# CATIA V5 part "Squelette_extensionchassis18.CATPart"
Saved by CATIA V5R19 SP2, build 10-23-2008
Part number: Squelette_extensionchassis18
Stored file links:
  G:\Documents\IFMA\COURS\2A\S3\CFAO\ProjetCFAO\Squelette_extensionchassis18.CATPart

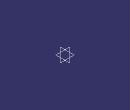
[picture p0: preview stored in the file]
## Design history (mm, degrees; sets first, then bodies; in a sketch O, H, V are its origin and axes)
Body1 (main body)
